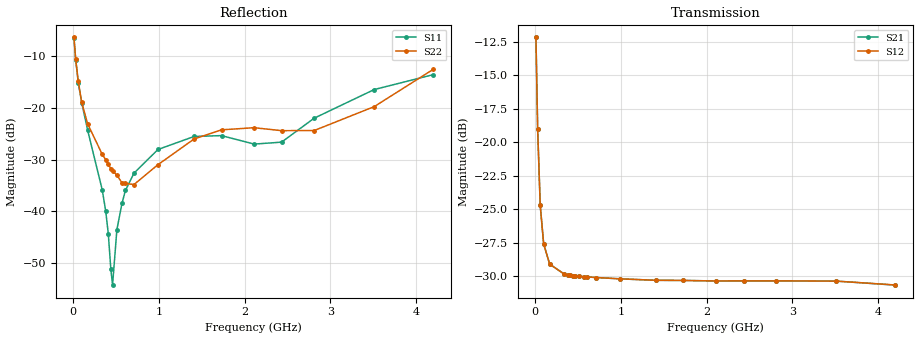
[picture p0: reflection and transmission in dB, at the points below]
! Integrated Device Technology
! Corporate Headquarters
! 6024 Silver Creek Valley Road
! San Jose, CA 95138  USA
! Phone:  1-408-284-8200
! Toll Free:  1-800-223-1366
! Webpage:  http://www.idt.com/
! Timing and RF Division
! 515 Groton Road, Suite 102
! Westford, MA 01886-6024
! Device:  F1950
! Description: 7-bit 0.25 dB Digital Step Attenuator
! Frequency:  150.0 -  4000.00 MHz
! Package:  4x4 mm Thin QFN Plastic Package: 24 pin
! Ports:  2 RF, 12 DC
!  Pin  1  = D0
!  Pin  2  = VDD
!  Pin  3  = Vmode
!  Pin  4  = GND
!  Pin  5  = RF1  =  Port 1
!  Pin  6  = GND
!  Pin  7  = GND
!  Pin  8  = GND
!  Pin  9  = GND
!  Pin 10  = GND
!  Pin 11  = GND
!  Pin 12  = GND
!  Pin 13  = GND
!  Pin 14  = RF2  =  Port 2
!  Pin 15  = GND
!  Pin 16  = LE
!  Pin 17  = CLK
!  Pin 18  = DATE
!  Pin 19  = D6
!  Pin 20  = D5
!  Pin 21  = D4
!  Pin 22  = D3
!  Pin 23  = D2
!  Pin 24  = D1
! State:  117
! Atten State:  29.25 dB
! Voltage:  +5.00 Volts
! Current:  Not Measured mA
! Data:  The device was measured on a the F195X evaluation board which has
!  individual transmission lines to the RF pins.  Data was collected
!  using a calibrated network analyzer.  The evaluation board was
!  de-embedded using a TRL calibration technique.
!  The reference plane is the edge of the package pin.
! Misc:  Board 2019
!  Action Tracker AT0250
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# GHz S dB R 50
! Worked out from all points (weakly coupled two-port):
!   420 points, 10 MHz to 4.2 GHz, reference 50 ohm
!   highest |S21| = -12.15 dB at 10 MHz (marker M1); lowest = -30.7 dB at 4.2 GHz (marker M2)
!   lowest |S11| = -54.3 dB at 460 MHz (marker M3), VSWR 1.00, Z = 49.8 - j0.0401 ohm
!   |S11| at or under -10 dB: 26.78 MHz to end of sweep
!   |S22| runs from -35.1 to -6.3 dB; largest |S21 - S12| = 7.2e-05
!   S11 on the Smith chart (normalised r, x): 10 MHz: 1.99, -1.16; 30 MHz: 1.28, -0.64; 60 MHz: 1.11, -0.36; 410 MHz: 1.00, -0.01; 4.2 GHz: 0.69, +0.17
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0.01  -6.46 -28.3  -12.15 -40.4  -12.15 -40.4  -6.30 -29.0
0.03  -10.62 -51.0  -19.03 -61.7  -19.03 -61.7  -10.49 -52.7
0.06  -15.04 -63.8  -24.72 -55.5  -24.72 -55.4  -14.79 -65.5
0.1  -18.91 -70.6  -27.60 -41.9  -27.60 -41.9  -18.86 -71.0
0.17  -24.31 -72.3  -29.11 -28.3  -29.11 -28.4  -23.07 -76.9
0.34  -35.85 -71.8  -29.85 -17.3  -29.86 -17.3  -28.96 -85.7
0.38  -39.93 -72.7  -29.91 -16.3  -29.91 -16.3  -30.01 -87.3
0.41  -44.28 -81.0  -29.94 -15.7  -29.94 -15.6  -30.89 -88.9
0.44  -51.21 -106.5  -29.97 -15.1  -29.97 -15.1  -31.71 -93.1
0.46  -54.27 -168.0  -29.99 -14.8  -29.99 -14.9  -32.12 -96.5
0.51  -43.56 140.9  -30.02 -14.3  -30.02 -14.3  -32.95 -102.4
0.57  -38.43 135.2  -30.05 -13.9  -30.05 -13.9  -34.46 -113.3
0.61  -35.94 136.6  -30.07 -13.7  -30.07 -13.7  -34.59 -121.7
0.71  -32.58 137.7  -30.11 -13.5  -30.11 -13.5  -34.79 -141.6
0.99  -28.00 146.8  -30.21 -14.1  -30.21 -14.1  -30.94 178.7
1.41  -25.49 162.1  -30.32 -15.9  -30.32 -15.9  -25.98 159.7
1.73  -25.32 167.1  -30.33 -17.6  -30.33 -17.6  -24.20 151.2
2.11  -26.96 156.3  -30.37 -20.5  -30.37 -20.5  -23.79 141.3
2.43  -26.59 124.9  -30.37 -22.4  -30.36 -22.4  -24.36 130.3
2.81  -21.95 104.6  -30.37 -25.5  -30.36 -25.5  -24.34 114.9
3.51  -16.40 116.8  -30.38 -30.6  -30.38 -30.7  -19.71 112.5
4.2  -13.51 145.1  -30.68 -33.3  -30.67 -33.4  -12.47 126.8
